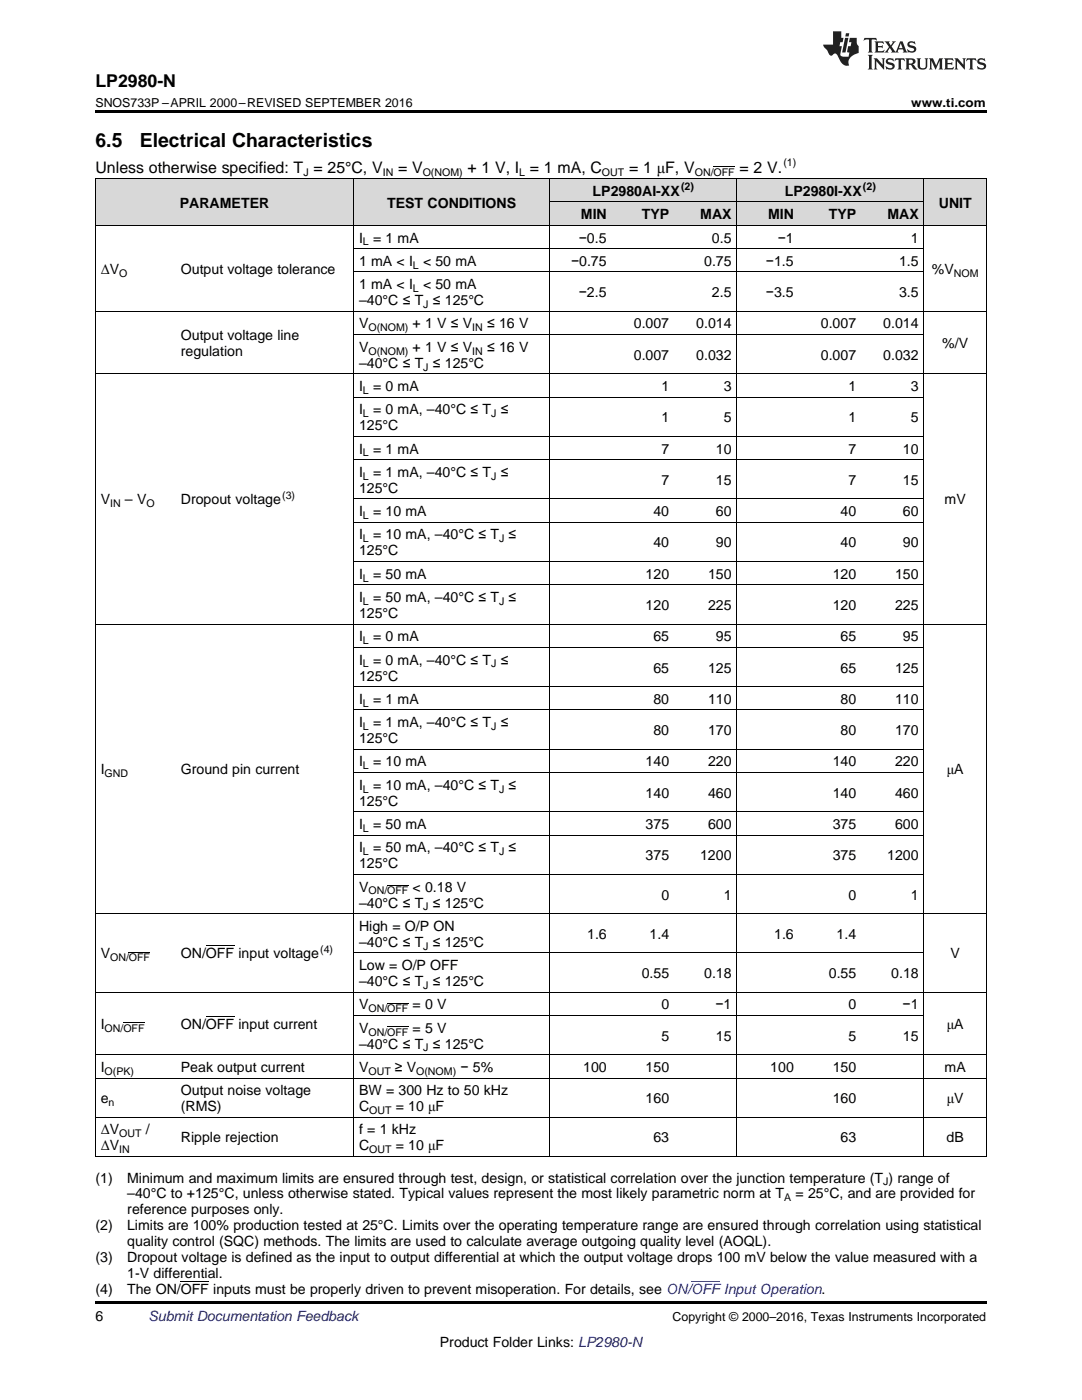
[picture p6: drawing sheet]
<svg xmlns="http://www.w3.org/2000/svg" width="216mm" height="279mm" viewBox="0 0 216 279" stroke-linecap="round" stroke-linejoin="round" font-family="sans-serif">
<defs><g id="words">
<g font-size="3.9">
<text x="19" y="29.3">6.5</text>
<text x="27.9" y="29.3">Electrical Characteristics</text>
</g>
<text font-size="3.5" x="19" y="17.3">LP2980-N</text>
<g font-size="3.2">
<text x="19" y="34.4">Unless otherwise specified: T = 25°C, V</text>
<text x="79.4" y="34.4">= V</text>
<text x="93.3" y="34.4">+ 1 V, I = 1 mA, C</text>
<text x="125.5" y="34.4">= 1 μF, V</text>
<text x="147.6" y="34.4">= 2 V.</text>
</g>
<g font-size="2.8">
<text x="35.9" y="41.4">PARAMETER</text>
<text x="77.3" y="41.4">TEST CONDITIONS</text>
<text x="118.3" y="39.1">LP2980AI-XX</text>
<text x="156.6" y="39.1">LP2980I-XX</text>
<text x="187.3" y="41.4">UNIT</text>
<text x="115.9" y="43.7">MIN</text>
<text x="128.1" y="43.7">TYP</text>
<text x="139.7" y="43.7">MAX</text>
<text x="153.2" y="43.7">MIN</text>
<text x="165.4" y="43.7">TYP</text>
<text x="177.1" y="43.7">MAX</text>
<text x="71.6" y="48.4">I</text>
<text x="71.6" y="53.1">1 mA &lt; I</text>
<text x="74.4" y="48.4">= 1 mA</text>
<text x="84.4" y="53.1">&lt; 50 mA</text>
<text x="113.9" y="53.1">−0.75</text>
<text x="115.5" y="48.4">−0.5</text>
<text x="140.5" y="53.1">0.75</text>
<text x="142.1" y="48.4">0.5</text>
<text x="152.8" y="53.1">−1.5</text>
<text x="155.2" y="48.4">−1</text>
<text x="179.4" y="53.1">1.5</text>
<text x="181.8" y="48.4">1</text>
<text x="20.1" y="54.6">ΔV</text>
<text x="36.1" y="54.6">Output voltage tolerance</text>
<text x="71.6" y="57.7">1 mA &lt; I</text>
<text x="84.4" y="57.7">&lt; 50 mA</text>
<text x="115.5" y="59.3">−2.5</text>
<text x="142.1" y="59.3">2.5</text>
<text x="152.8" y="59.3">−3.5</text>
<text x="179.4" y="59.3">3.5</text>
<text x="185.9" y="54.6">%V</text>
<text x="71.6" y="60.9">–40°C ≤ T ≤ 125°C</text>
<text x="71.6" y="65.5">V</text>
<text x="82.3" y="65.5">+ 1 V ≤ V</text>
<text x="97.2" y="65.5">≤ 16 V</text>
<text x="126.5" y="65.5">0.007</text>
<text x="138.9" y="65.5">0.014</text>
<text x="163.8" y="65.5">0.007</text>
<text x="176.2" y="65.5">0.014</text>
<text x="36.1" y="67.9">Output voltage line</text>
<text x="36.1" y="71">regulation</text>
<text x="71.6" y="70.2">V</text>
<text x="82.3" y="70.2">+ 1 V ≤ V</text>
<text x="97.2" y="70.2">≤ 16 V</text>
<text x="126.5" y="71.8">0.007</text>
<text x="138.9" y="71.8">0.032</text>
<text x="163.8" y="71.8">0.007</text>
<text x="176.2" y="71.8">0.032</text>
<text x="188" y="69.5">%/V</text>
<text x="71.6" y="73.4">–40°C ≤ T ≤ 125°C</text>
<text x="71.6" y="78">I</text>
<text x="71.6" y="82.7">I</text>
<text x="74.4" y="78">= 0 mA</text>
<text x="74.4" y="82.7">= 0 mA, –40°C ≤ T ≤</text>
<text x="132" y="78">1</text>
<text x="144.4" y="78">3</text>
<text x="169.3" y="78">1</text>
<text x="181.8" y="78">3</text>
<text x="71.6" y="85.9">125°C</text>
<text x="132" y="84.3">1</text>
<text x="144.4" y="84.3">5</text>
<text x="169.3" y="84.3">1</text>
<text x="181.8" y="84.3">5</text>
<text x="71.6" y="90.5">I</text>
<text x="71.6" y="95.2">I</text>
<text x="74.4" y="90.5">= 1 mA</text>
<text x="74.4" y="95.2">= 1 mA, –40°C ≤ T ≤</text>
<text x="132" y="90.5">7</text>
<text x="142.8" y="90.5">10</text>
<text x="169.3" y="90.5">7</text>
<text x="180.2" y="90.5">10</text>
<text x="20.1" y="100.7">V</text>
<text x="24.9" y="100.7">– V</text>
<text x="36.1" y="100.7">Dropout voltage</text>
<text x="71.6" y="98.4">125°C</text>
<text x="132" y="96.8">7</text>
<text x="142.8" y="96.8">15</text>
<text x="169.3" y="96.8">7</text>
<text x="180.2" y="96.8">15</text>
<text x="188.5" y="100.7">mV</text>
<text x="71.6" y="103">I</text>
<text x="71.6" y="107.7">I</text>
<text x="74.4" y="103">= 10 mA</text>
<text x="74.4" y="107.7">= 10 mA, –40°C ≤ T ≤</text>
<text x="130.4" y="103">40</text>
<text x="142.8" y="103">60</text>
<text x="167.7" y="103">40</text>
<text x="180.2" y="103">60</text>
<text x="71.6" y="110.8">125°C</text>
<text x="130.4" y="109.3">40</text>
<text x="142.8" y="109.3">90</text>
<text x="167.7" y="109.3">40</text>
<text x="180.2" y="109.3">90</text>
<text x="71.6" y="115.5">I</text>
<text x="74.4" y="115.5">= 50 mA</text>
<text x="128.8" y="115.5">120</text>
<text x="141.3" y="115.5">150</text>
<text x="166.2" y="115.5">120</text>
<text x="178.6" y="115.5">150</text>
<text x="71.6" y="120.2">I</text>
<text x="71.6" y="123.3">125°C</text>
<text x="74.4" y="120.2">= 50 mA, –40°C ≤ T ≤</text>
<text x="128.8" y="121.7">120</text>
<text x="141.3" y="121.7">225</text>
<text x="166.2" y="121.7">120</text>
<text x="178.6" y="121.7">225</text>
<text x="71.6" y="128">I</text>
<text x="74.4" y="128">= 0 mA</text>
<text x="130.4" y="128">65</text>
<text x="142.8" y="128">95</text>
<text x="167.7" y="128">65</text>
<text x="180.2" y="128">95</text>
<text x="71.6" y="132.6">I</text>
<text x="71.6" y="135.8">125°C</text>
<text x="74.4" y="132.6">= 0 mA, –40°C ≤ T ≤</text>
<text x="130.4" y="134.2">65</text>
<text x="141.3" y="134.2">125</text>
<text x="167.7" y="134.2">65</text>
<text x="178.6" y="134.2">125</text>
<text x="71.6" y="140.5">I</text>
<text x="74.4" y="140.5">= 1 mA</text>
<text x="130.4" y="140.5">80</text>
<text x="141.3" y="140.5">110</text>
<text x="167.7" y="140.5">80</text>
<text x="178.6" y="140.5">110</text>
<text x="71.6" y="145.1">I</text>
<text x="71.6" y="148.3">125°C</text>
<text x="74.4" y="145.1">= 1 mA, –40°C ≤ T ≤</text>
<text x="130.4" y="146.7">80</text>
<text x="141.3" y="146.7">170</text>
<text x="167.7" y="146.7">80</text>
<text x="178.6" y="146.7">170</text>
<text x="20.1" y="154.6">I</text>
<text x="36.1" y="154.6">Ground pin current</text>
<text x="71.6" y="153">I</text>
<text x="74.4" y="153">= 10 mA</text>
<text x="128.8" y="153">140</text>
<text x="141.3" y="153">220</text>
<text x="166.2" y="153">140</text>
<text x="178.6" y="153">220</text>
<text x="188.9" y="154.6">μA</text>
<text x="71.6" y="157.6">I</text>
<text x="71.6" y="160.8">125°C</text>
<text x="74.4" y="157.6">= 10 mA, –40°C ≤ T ≤</text>
<text x="128.8" y="159.2">140</text>
<text x="141.3" y="159.2">460</text>
<text x="166.2" y="159.2">140</text>
<text x="178.6" y="159.2">460</text>
<text x="71.6" y="165.5">I</text>
<text x="74.4" y="165.5">= 50 mA</text>
<text x="128.8" y="165.5">375</text>
<text x="141.3" y="165.5">600</text>
<text x="166.2" y="165.5">375</text>
<text x="178.6" y="165.5">600</text>
<text x="71.6" y="170.1">I</text>
<text x="71.6" y="173.3">125°C</text>
<text x="74.4" y="170.1">= 50 mA, –40°C ≤ T ≤</text>
<text x="128.8" y="171.7">375</text>
<text x="139.7" y="171.7">1200</text>
<text x="166.2" y="171.7">375</text>
<text x="177" y="171.7">1200</text>
<text x="71.6" y="177.9">V</text>
<text x="82.3" y="177.9">&lt; 0.18 V</text>
<text x="132" y="179.5">0</text>
<text x="144.4" y="179.5">1</text>
<text x="169.3" y="179.5">0</text>
<text x="181.8" y="179.5">1</text>
<text x="71.6" y="181.1">–40°C ≤ T ≤ 125°C</text>
<text x="71.6" y="185.8">High = O/P ON</text>
<text x="20.1" y="191.3">V</text>
<text x="36.1" y="191.3">ON/OFF input voltage</text>
<text x="71.6" y="188.9">–40°C ≤ T ≤ 125°C</text>
<text x="117.2" y="187.4">1.6</text>
<text x="129.6" y="187.4">1.4</text>
<text x="154.5" y="187.4">1.6</text>
<text x="166.9" y="187.4">1.4</text>
<text x="189.7" y="191.3">V</text>
<text x="71.6" y="193.6">Low = O/P OFF</text>
<text x="71.6" y="196.8">–40°C ≤ T ≤ 125°C</text>
<text x="128.1" y="195.2">0.55</text>
<text x="140.5" y="195.2">0.18</text>
<text x="165.4" y="195.2">0.55</text>
<text x="177.8" y="195.2">0.18</text>
<text x="71.6" y="201.4">V</text>
<text x="82.3" y="201.4">= 0 V</text>
<text x="132" y="201.4">0</text>
<text x="142.8" y="201.4">−1</text>
<text x="169.3" y="201.4">0</text>
<text x="180.1" y="201.4">−1</text>
<text x="20.1" y="205.4">I</text>
<text x="36.1" y="205.4">ON/OFF input current</text>
<text x="71.6" y="206.1">V</text>
<text x="71.6" y="209.3">–40°C ≤ T ≤ 125°C</text>
<text x="82.3" y="206.1">= 5 V</text>
<text x="132" y="207.7">5</text>
<text x="142.8" y="207.7">15</text>
<text x="169.3" y="207.7">5</text>
<text x="180.2" y="207.7">15</text>
<text x="188.9" y="205.4">μA</text>
<text x="20.1" y="213.9">I</text>
<text x="36.1" y="213.9">Peak output current</text>
<text x="71.6" y="213.9">V</text>
<text x="78.8" y="213.9">≥ V</text>
<text x="91.9" y="213.9">− 5%</text>
<text x="116.4" y="213.9">100</text>
<text x="128.8" y="213.9">150</text>
<text x="153.7" y="213.9">100</text>
<text x="166.2" y="213.9">150</text>
<text x="188.5" y="213.9">mA</text>
<text x="20.1" y="220.2">e</text>
<text x="36.1" y="218.6">Output noise voltage</text>
<text x="36.1" y="221.8">(RMS)</text>
<text x="71.6" y="218.6">BW = 300 Hz to 50 kHz</text>
<text x="71.6" y="221.8">C</text>
<text x="79" y="221.8">= 10 μF</text>
<text x="128.8" y="220.2">160</text>
<text x="166.2" y="220.2">160</text>
<text x="188.9" y="220.2">μV</text>
<text x="20.1" y="226.4">ΔV</text>
<text x="29.1" y="226.4">/</text>
<text x="71.6" y="226.4">f = 1 kHz</text>
<text x="20.1" y="229.6">ΔV</text>
<text x="36.1" y="228">Ripple rejection</text>
<text x="71.6" y="229.6">C</text>
<text x="79" y="229.6">= 10 μF</text>
<text x="130.4" y="228">63</text>
<text x="167.7" y="228">63</text>
<text x="188.9" y="228">dB</text>
<text x="19" y="236">(1)</text>
<text x="25.4" y="236">Minimum and maximum limits are ensured through test, design, or statistical correlation over the junction temperature (T ) range of</text>
<text x="25.4" y="239.2">–40°C to +125°C, unless otherwise stated. Typical values represent the most likely parametric norm at T</text>
<text x="158.7" y="239.2">= 25°C, and are provided for</text>
<text x="19" y="245.5">(2)</text>
<text x="25.4" y="245.5">Limits are 100% production tested at 25°C. Limits over the operating temperature range are ensured through correlation using statistical</text>
<text x="25.4" y="242.4">reference purposes only.</text>
<text x="19" y="251.9">(3)</text>
<text x="25.4" y="251.9">Dropout voltage is defined as the input to output differential at which the output voltage drops 100 mV below the value measured with a</text>
<text x="25.4" y="248.7">quality control (SQC) methods. The limits are used to calculate average outgoing quality level (AOQL).</text>
<text x="25.4" y="255.1">1-V differential.</text>
<text x="19" y="263.6">6</text>
<text x="19" y="258.2">(4)</text>
<text x="25.4" y="258.2">The ON/OFF inputs must be properly driven to prevent misoperation. For details, see ON/OFF Input Operation.</text>
<text x="87.8" y="268.9">Product Folder Links: LP2980-N</text>
</g>
<text font-size="2.8" fill="#0000c8" x="29.6" y="263.6">Submit Documentation Feedback</text>
<g font-size="2.5">
<text x="19" y="21.4">SNOS733P –APRIL 2000–REVISED SEPTEMBER 2016</text>
<text x="181.8" y="21.4">www.ti.com</text>
<text x="134.2" y="263.6">Copyright © 2000–2016, Texas Instruments Incorporated</text>
</g>
<g font-size="2.1">
<text x="60.5" y="35.1">J</text>
<text x="76.4" y="35.1">IN</text>
<text x="84.3" y="35.1">O(NOM)</text>
<text x="103.6" y="35.1">L</text>
<text x="120.1" y="35.1">OUT</text>
<text x="138.6" y="35.1">ON/OFF</text>
<text x="156.3" y="33.2">(1)</text>
<text x="135.9" y="38">(2)</text>
<text x="172.2" y="38">(2)</text>
<text x="72.4" y="49">L</text>
<text x="82.4" y="53.6">L</text>
<text x="23.8" y="55.2">O</text>
<text x="82.4" y="58.3">L</text>
<text x="190.3" y="55.2">NOM</text>
<text x="84.5" y="61.5">J</text>
<text x="73.5" y="66.1">O(NOM)</text>
<text x="73.5" y="70.8">O(NOM)</text>
<text x="94.2" y="66.1">IN</text>
<text x="94.2" y="70.8">IN</text>
<text x="84.5" y="73.9">J</text>
<text x="72.4" y="78.6">L</text>
<text x="72.4" y="83.3">L</text>
<text x="98" y="83.3">J</text>
<text x="72.4" y="91.1">L</text>
<text x="72.4" y="95.7">L</text>
<text x="98" y="95.7">J</text>
<text x="22" y="101.2">IN</text>
<text x="29.2" y="101.2">O</text>
<text x="56.3" y="99.6">(3)</text>
<text x="72.4" y="103.6">L</text>
<text x="72.4" y="108.2">L</text>
<text x="99.6" y="108.2">J</text>
<text x="72.4" y="116.1">L</text>
<text x="72.4" y="120.7">L</text>
<text x="99.6" y="120.7">J</text>
<text x="72.4" y="128.6">L</text>
<text x="72.4" y="133.2">L</text>
<text x="98" y="133.2">J</text>
<text x="72.4" y="141">L</text>
<text x="72.4" y="145.7">L</text>
<text x="98" y="145.7">J</text>
<text x="20.9" y="155.1">GND</text>
<text x="72.4" y="153.5">L</text>
<text x="72.4" y="158.2">L</text>
<text x="99.6" y="158.2">J</text>
<text x="72.4" y="166">L</text>
<text x="72.4" y="170.7">L</text>
<text x="99.6" y="170.7">J</text>
<text x="73.5" y="178.5">ON/OFF</text>
<text x="84.5" y="181.7">J</text>
<text x="22" y="191.8">ON/OFF</text>
<text x="63.9" y="190.1">(4)</text>
<text x="84.5" y="189.5">J</text>
<text x="84.5" y="197.3">J</text>
<text x="73.5" y="202">ON/OFF</text>
<text x="20.9" y="205.9">ON/OFF</text>
<text x="73.5" y="206.7">ON/OFF</text>
<text x="84.5" y="209.8">J</text>
<text x="20.9" y="214.5">O(PK)</text>
<text x="73.5" y="214.5">OUT</text>
<text x="83" y="214.5">O(NOM)</text>
<text x="21.7" y="220.7">n</text>
<text x="23.8" y="227">OUT</text>
<text x="73.7" y="222.3">OUT</text>
<text x="23.8" y="230.2">IN</text>
<text x="73.7" y="230.2">OUT</text>
<text x="156.5" y="239.7">A</text>
<text x="176.2" y="236.6">J</text>
</g>
</g></defs>
<g fill="#d8d8d8">
<path d="M19 35.7h16v9.3h-16z"/>
<path d="M35 35.7h35.6v9.3h-35.6z"/>
<path d="M70.6 35.7h39.1v9.3h-39.1z"/>
<path d="M184.4 35.7h12.4v9.3h-12.4z"/>
<path d="M109.7 40.4h12.5v4.6h-12.5z"/>
<path d="M122.2 40.4h12.4v4.6h-12.4z"/>
<path d="M134.6 40.4h12.4v4.6h-12.4z"/>
<path d="M147 40.4h12.5v4.6h-12.5z"/>
<path d="M159.5 40.4h12.4v4.6h-12.4z"/>
<path d="M171.9 40.4h12.5v4.6h-12.5z"/>
<path d="M109.7 35.7h12.5v4.7h-12.5z"/>
<path d="M122.2 35.7h12.4v4.7h-12.4z"/>
<path d="M134.6 35.7h12.4v4.7h-12.4z"/>
<path d="M147 35.7h12.5v4.7h-12.5z"/>
<path d="M159.5 35.7h12.4v4.7h-12.4z"/>
<path d="M171.9 35.7h12.5v4.7h-12.5z"/>
</g>
<path d="M19 22h177.8v.5h-177.8zM19 259.7h177.8v.5h-177.8z" fill="#000"/>
<g fill="none" stroke="#000" stroke-width=".2">
<path d="M19 35.6l177.8 .1v195.2M19.1 35.7v195.2M70.5 35.7v195.2M109.7 35.7v195.2M147 35.7v195.2M184.3 35.7v195.2M19 45h177.8M70.6 54.3h113.8M70.6 49.6h113.8M109.7 40.3h74.7M19 74.6h177.8M19 62.1h177.8"/>
<path d="M70.6 79.3h113.8M70.6 66.8h113.8M70.6 99.6h113.8M70.6 91.7h113.8M70.6 87.1h113.8M70.6 116.7h113.8M70.6 112.1h113.8M70.6 104.2h113.8M19 124.5h177.8M70.6 137h113.8M70.6 129.2h113.8M70.6 154.2h113.8"/>
<path d="M70.6 149.5h113.8M70.6 141.7h113.8M70.6 174.5h113.8M70.6 166.7h113.8M70.6 162h113.8M19 198h177.8M19 182.3h177.8M70.6 190.2h113.8M19 215.1h177.8M19 210.5h177.8M70.6 202.7h113.8M19 230.8h177.8"/>
<path d="M19 223h177.8"/>
</g>
<g fill="#231f20">
<path d="M172.5 7.6l-.1 .5 .4-.2h.6v.1v2.1l-.2 .4h.9l-.2-.4v-2.1l.1-.1h.5l.5 .2-.2-.5zM174.5 8.3l.2 .3v1.5l-.2 .4h1.8l.2-.6a1.04 1.04 0 0 1-1.3 .2v-.7h.6l.3 .2v-.6l-.3 .2h-.6v-.6l.8-.1 .4 .3-.2-.5zM176.5 8.3l.9 1.1-.9 1.1h.8l-.2-.2 .4-.7 .5 .7-.2 .2h1.5l-.2-.2 .2-.4h.9l.1 .4-.2 .2h1l-.3-.3-.7-1.9h-.5l-.9 2-.8-1 .9-1h-.8l.1 .3-.4 .5-.3-.6 .1-.2zM179.7 8.6l.4 1h-.7zM181.3 8.4a.63 .63 0 0 0-.2 .7 .63 .63 0 0 0 .6 .4l.6 .2 .1 .2a.75 .75 0 0 1-.7 .4 .75 .75 0 0 1-.6-.5l.1 .7 .1-.1a1.11 1.11 0 0 0 1.5-.6 1.13 1.13 0 0 0-1.2-.8l-.1-.4a1.04 1.04 0 0 1 1.2 .2l-.2-.5-.2 .1-.4-.2zM173.2 10.9l.2 .4v2.2l-.2 .4h1l-.3-.4v-2.2l.3-.4zM174.3 11.6l.3 .4v1.5l-.3 .4h.8l-.2-.4v-1.3l1.5 1.7v-1.9l.2-.4h-.7l.2 .4v.9l-1.1-1.3zM177 11.8a.62 .62 0 0 0-.2 .7 .62 .62 0 0 0 .6 .4l.6 .1 .1 .3a.76 .76 0 0 1-.7 .3 .76 .76 0 0 1-.7-.4l.2 .7 .1-.1a1.11 1.11 0 0 0 1.5-.6 1.13 1.13 0 0 0-1.2-.8l-.1-.4a1.04 1.04 0 0 1 1.2 .2l-.2-.6-.2 .1-.5-.1zM178.7 11.6l-.2 .6a.61 .61 0 0 1 .8-.3v1.6l-.2 .4h.9l-.2-.4v-1.6a.63 .63 0 0 1 .7 .3l-.1-.6zM180.6 11.6l.3 .4v1.5l-.3 .4h1l-.2-.2-.1-.8 .6 .2a.76 .76 0 0 0 1.2 .7l-1-1a.58 .58 0 0 0 .6-.5 .58 .58 0 0 0-.5-.6zM181.4 11.9h.1a.45 .45 0 0 1 .5 .1 .45 .45 0 0 1 .1 .5l-.8 .2zM182.9 11.6l.2 .2a2.17 2.17 0 0 0 .3 1.9 .99 .99 0 0 0 1.6-.6v-1.1l.2-.4h-.7l.2 .2a1.92 1.92 0 0 1-.2 1.8 .6 .6 0 0 1-.9-.5v-1.1l.2-.4zM185.4 11.6l.2 .4v1.5l-.2 .4h.7l-.2-.4v-1.4l.8 1.8 .8-1.8v1.4l-.2 .4h.9l-.2-.4v-1.5l.2-.4h-.8l-.6 1.5-.6-1.5zM188.4 11.6l.2 .4v1.5l-.2 .4h1.8l.1-.6a1.04 1.04 0 0 1-1.2 .1v-.6h.5l.4 .2v-.6l-.4 .2h-.5v-.7h.8l.3 .3-.1-.6zM190.5 11.6l.2 .4v1.5l-.2 .4h.7l-.2-.4v-1.3l1.5 1.7v-1.9l.2-.4h-.7l.2 .4v.9l-1.1-1.3zM192.9 11.6l-.1 .6a.61 .61 0 0 1 .7-.3l.1 1.6-.3 .4h1l-.3-.4 .1-1.6a.63 .63 0 0 1 .7 .3l-.1-.6zM195.2 11.8a.62 .62 0 0 0-.2 .7 .62 .62 0 0 0 .6 .4l.6 .1 .1 .3a.76 .76 0 0 1-.7 .3 .76 .76 0 0 1-.6-.4l.1 .7 .1-.1a1.11 1.11 0 0 0 1.6-.6 1.13 1.13 0 0 0-1.3-.8l-.1-.4a1.04 1.04 0 0 1 1.2 .2l-.1-.6-.2 .1-.5-.1z"/>
<path d="M166.2 6.3v2.6h-1.9v.4l.8 .9a.91 .91 0 0 0 1 .8 .56 .56 0 0 1 .5-.3 .56 .56 0 0 1 .5 .3l.4 .8a1.53 1.53 0 0 0 1.9 1.2 1.54 1.54 0 0 1 1-2.1l.9-.3v-1.4a1.52 1.52 0 0 1-.4-1.6h-1.3l-.2 .8h.5l-.2 .8h-.5l-.1 1v.2l.4 .1-.2 .8a1.93 1.93 0 0 1-1.6-.3l.3-1.8h-.5l.2-.8h.4l.2-.8h-.4v-1.3zM168.6 7.6l-.6 2.9h.7l.6-2.9zM168.8 6.6l-.1 .7h.6l.2-.7z"/>
</g>
<path d="M137.9 255.7h5.7" fill="none" stroke="#00f" stroke-width=".2"/>
<path d="M142.4 33.3h4.2M77.3 176.7h4.2M25.7 190h4.3M41.1 188.8h5.6M24.6 204.1h4.3M41.1 202.9h5.6M77.3 204.8h4.2M77.3 200.2h4.2M36.1 255.7h5.6" fill="none" stroke="#000" stroke-width=".2"/>
<use href="#words"/>
</svg>
